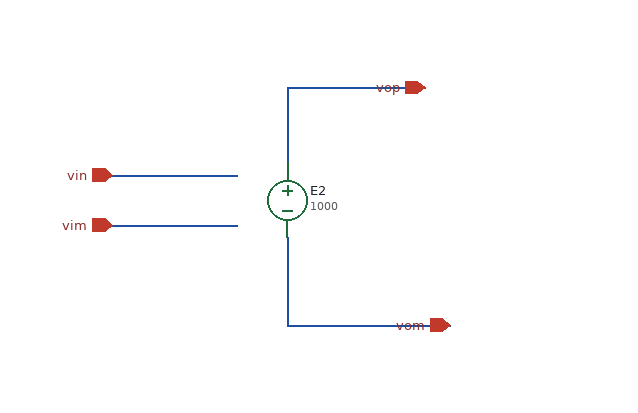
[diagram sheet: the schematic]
v {xschem version=3.4.8RC file_version=1.2}
G {}
K {}
V {}
S {}
E {}
N -230 -190 -230 -130 {lab=vop}
N -230 -190 -120 -190 {lab=vop}
N -370 -120 -270 -120 {lab=vin}
N -370 -80 -270 -80 {lab=vim}
N -230 -70 -230 -0 {lab=xxx}
N -230 -0 -100 -0 {lab=xxx}
C {vcvs.sym} -230 -100 0 0 {name=E2 value=1000}
C {iopin.sym} -100 0 0 0 {name=p25 lab=vom}
C {iopin.sym} -370 -120 2 0 {name=p27 lab=vin}
C {iopin.sym} -370 -80 2 0 {name=p28 lab=vim}
C {iopin.sym} -120 -190 0 0 {name=p1 lab=vop}
